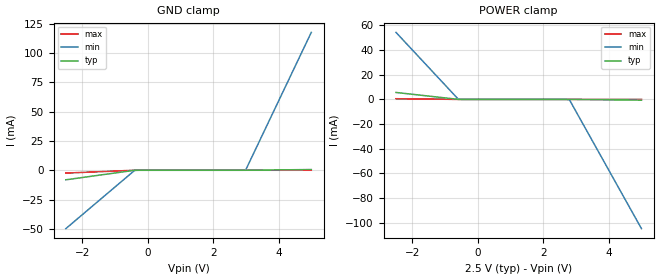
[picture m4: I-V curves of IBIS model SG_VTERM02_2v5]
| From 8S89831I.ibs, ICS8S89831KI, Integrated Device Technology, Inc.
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[Model] SG_VTERM02_2v5
Model_type   Input
Polarity   Non-Inverting
Vinl = 1.65V
Vinh = 1.65V
|   typ   min   max
C_comp   2pF   1.5pF   2.5pF
|   typ   min   max
[Voltage range]   2.5V   2.375V   2.625V
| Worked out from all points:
|   GND clamp passes 1 mA (typ) near -0.65 V on its own axis
|   POWER clamp passes 1 mA (typ) near -0.93 V on its own axis
[GND_clamp]
|Voltage   I (typ)   I (min)   I (max)
-2.5V     -8.159mA   -49.85mA   -2.43mA
-400mV    -29.55uA   -178.1uA   -3.029uA
3V        2.173uA    473.2uA    173.3pA
5V        592.8uA    117.6mA    209.3nA
[Power_clamp]
|Voltage   I (typ)   I (min)   I (max)
-2.5V     5.627mA    54.33mA    542.3uA
-600mV    31.7uA     269.1uA    1.296uA
2.8V      -1.074uA   -347.3uA   -71.25pA
5V        -627.6uA   -104.8mA   -201.3nA
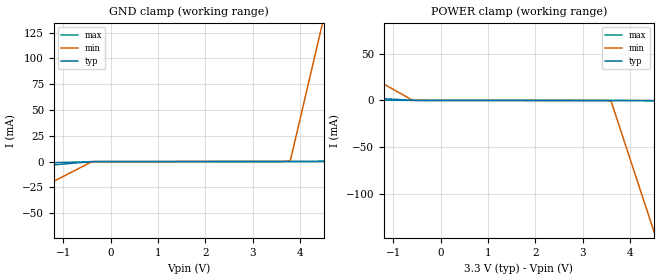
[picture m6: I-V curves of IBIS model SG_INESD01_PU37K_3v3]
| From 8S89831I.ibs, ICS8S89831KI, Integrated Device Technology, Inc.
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[Model] SG_INESD01_PU37K_3v3
Model_type   Input
Polarity   Non-Inverting
Vinl = 0.8V
Vinh = 2.0V
|   typ   min   max
C_comp   2pF   1.5pF   2.5pF
|   typ   min   max
[Voltage range]   3.3V   3.135V   3.465V
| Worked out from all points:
|   GND clamp passes 1 mA (typ) near -0.62 V on its own axis
|   POWER clamp passes 1 mA (typ) near -0.92 V on its own axis
[GND_clamp]
|Voltage   I (typ)   I (min)   I (max)
-3.3V     -11.43mA   -68.9mA    -3.59mA
-400mV    -127.7uA   -247.7uA   -137.2uA
3.6V      7.948uA    21.58uA    4.678uA
3.8V      15.41uA    1.248mA    11.61uA
4.4V      208.5uA    118.8mA    32.41uA
4.5V      240.7uA    138.4mA    35.88uA
6.6V      916.4uA    549.7mA    108.7uA
[Power_clamp]
|Voltage   I (typ)   I (min)   I (max)
-3.3V     8.07mA     77.15mA    884.4uA
-600mV    47.59uA    280.9uA    22.09uA
3.4V      -90.14uA   -70.79uA   -118uA
3.6V      -96.53uA   -1.068mA   -124.9uA
4.5V      -376.8uA   -139.9mA   -156.2uA
4.6V      -407.9uA   -155.3mA   -159.7uA
6.6V      -1.031mA   -463.8mA   -229.3uA
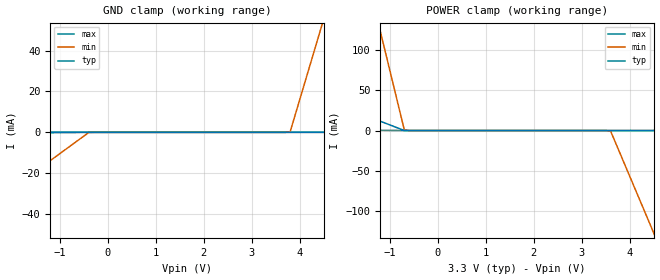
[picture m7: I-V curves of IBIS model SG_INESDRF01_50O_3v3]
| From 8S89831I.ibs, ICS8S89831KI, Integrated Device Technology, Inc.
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[Model] SG_INESDRF01_50O_3v3
Model_type   Input
Polarity   Non-Inverting
Vinl = 0.8V
Vinh = 2.0V
|   typ   min   max
C_comp   2pF   1.5pF   2.5pF
|   typ   min   max
[Voltage range]   3.3V   3.135V   3.465V
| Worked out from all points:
|   POWER clamp passes 1 mA (typ) near -0.74 V on its own axis
[GND_clamp]
|Voltage   I (typ)   I (min)   I (max)
-3.3V     -547.9uA   -49.76mA   -354.4nA
-400mV    -393.2nA   -69.82uA   -94.11pA
3.8V      19.97nA    321uA      15.87pA
4.4V      5.769uA    47.58mA    23.32pA
4.5V      6.727uA    55.46mA    24.56pA
6.6V      26.85uA    220.9mA    50.61pA
[Power_clamp]
|Voltage   I (typ)   I (min)   I (max)
-3.3V     59.92mA    637.5mA    1.293mA
-1.3V     13.86mA    147.9mA    298.7uA
-1.2V     11.56mA    123.4mA    249uA
-700mV    47.95uA    997.7uA    345.1nA
-500mV    19.97nA    1.53uA     33.25pA
3.6V      -8.028nA   -573.7uA   -7.74pA
4.5V      -3.474uA   -127.3mA   -13.35pA
4.6V      -3.859uA   -141.4mA   -13.97pA
6.6V      -11.56uA   -422.9mA   -26.43pA
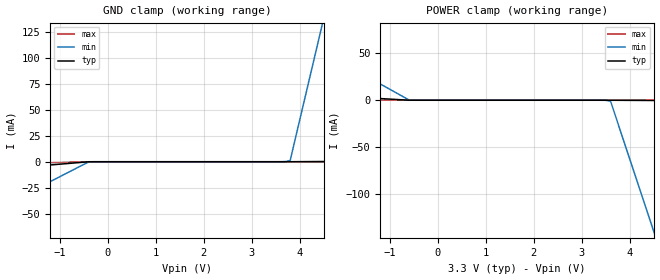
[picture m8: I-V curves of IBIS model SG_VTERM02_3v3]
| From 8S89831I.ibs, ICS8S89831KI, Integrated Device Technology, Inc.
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[Model] SG_VTERM02_3v3
Model_type   Input
Polarity   Non-Inverting
Vinl = 0.8V
Vinh = 2.0V
|   typ   min   max
C_comp   2pF   1.5pF   2.5pF
|   typ   min   max
[Voltage range]   3.3V   3.135V   3.465V
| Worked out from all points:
|   GND clamp passes 1 mA (typ) near -0.65 V on its own axis
|   POWER clamp passes 1 mA (typ) near -0.93 V on its own axis
[GND_clamp]
|Voltage   I (typ)   I (min)   I (max)
-3.3V     -11.26mA   -68.77mA   -3.355mA
-400mV    -29.55uA   -178.1uA   -3.029uA
3.6V      3.795nA    12.44uA    18.42pA
3.8V      2.173uA    1.235mA    47.63pA
4.4V      179.4uA    118.7mA    12nA
4.5V      208.9uA    138.3mA    13.99nA
6.6V      829uA      549.6mA    55.82nA
[Power_clamp]
|Voltage   I (typ)   I (min)   I (max)
-3.3V     7.982mA    77.09mA    770uA
-600mV    31.7uA     269.1uA    1.296uA
3.4V      -481.9pA   -3.883uA   -9.869pA
3.6V      -1.074uA   -996.9uA   -19.43pA
4.5V      -257.4uA   -139.8mA   -11.43nA
4.6V      -285.9uA   -155.2mA   -12.7nA
6.6V      -855.4uA   -463.7mA   -38.05nA
